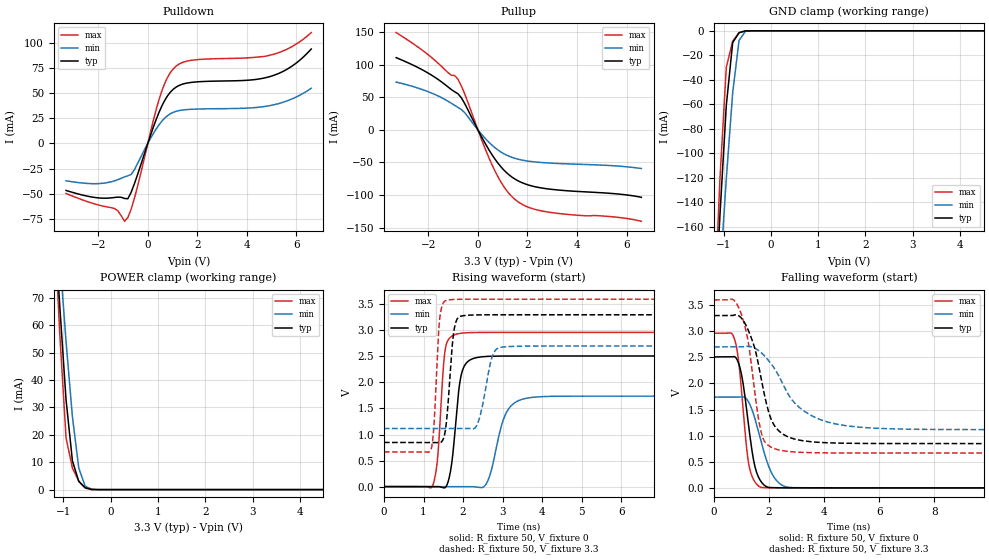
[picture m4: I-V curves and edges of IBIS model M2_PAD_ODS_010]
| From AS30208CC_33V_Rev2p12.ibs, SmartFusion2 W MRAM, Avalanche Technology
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[Model] M2_PAD_ODS_010
Model_type I/O
Enable   Active-High
Vinl  =  0.8
Vinh  =  2.2
Vmeas =  1.65
Cref  =  30e-12
| Capacitance  typ   min   max
C_comp   1.518749e-12   1.424706e-12   1.652746e-12
| Variables   typ   min   max
[GND Clamp Reference]   0   0   0
[POWER Clamp Reference]   3.3   2.7   3.6
[Pulldown Reference]   0   0   0
[Pullup Reference]   3.3   2.7   3.6
[Temperature Range]   25   125   -40
[Voltage Range]   3.3   2.7   3.6
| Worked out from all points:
|   slope of the pulldown table from 0 to 0.495 V, typ, clamps not added: 14.9 ohm
|   slope of the pullup table from 0 to 0.495 V, typ, clamps not added: 14.7 ohm
|   GND clamp passes 1 mA (typ) near -0.62 V on its own axis
|   POWER clamp passes 1 mA (typ) near -0.56 V on its own axis
|   falling waveform, R_fixture 50, V_fixture 0: 20-80 % time 394ps typ, 590ps min, 315ps max; typ from 2.51 V to 0 V
|   falling waveform, R_fixture 50, V_fixture 3.3: 20-80 % time 660ps typ, 1.32ns min, 479ps max; typ from 3.3 V to 0.848 V
|   rising waveform, R_fixture 50, V_fixture 0: 20-80 % time 197ps typ, 348ps min, 149ps max; typ from 0 V to 2.51 V
|   rising waveform, R_fixture 50, V_fixture 3.3: 20-80 % time 147ps typ, 240ps min, 115ps max; typ from 0.848 V to 3.3 V
[GND Clamp]
| Voltage   I(typ)   I(min)   I(max)
-3.3V     -1.961A    -1.697A    -2.357A
-1.21V    -250.7mA   -283.7mA   -242.5mA
-1.076V   -150.6mA   -200.1mA   -120.7mA
-941.4mV  -60.83mA   -120.8mA   -29.76mA
-806.9mV  -9.649mA   -50.71mA   -8.442mA
-672.4mV  -1.587mA   -7.866mA   -1.46mA
-537.9mV  -71.93uA   -504.3uA   -18.83uA
-403.4mV  -595.6nA   -18.58uA   -37.45nA
6.6V      0A         0A         0A
[POWER Clamp]
| Voltage   I(typ)   I(min)   I(max)
-3.3V     772.3mA    673.3mA    930.5mA
-1.21V    105.9mA    117.6mA    104.6mA
-1.076V   67.34mA    85.06mA    57.16mA
-941.4mV  32.71mA    53.93mA    18.82mA
-806.9mV  10.48mA    26.53mA    7.848mA
-672.4mV  2.975mA    7.856mA    3.108mA
-537.9mV  710.9uA    1.248mA    573.1uA
-403.4mV  60.69uA    160.8uA    9.187uA
-269mV    142.4nA    6.118uA    23.26nA
6.6V      0A         0A         0A
[Pulldown]
| Voltage   I(typ)   I(min)   I(max)
-3.3V     -46.77mA   -37.16mA   -49.83mA
-1.345V   -53.76mA   -37.21mA   -64.77mA
-941.4mV  -54.71mA   -33.33mA   -77.43mA
-806.9mV  -55.02mA   -32.17mA   -73.73mA
-537.9mV  -39.9mA    -25.92mA   -54.28mA
455.2mV   31.02mA    18.55mA    43.7mA
682.8mV   42.73mA    25.18mA    59.65mA
1.024V    53.77mA    30.89mA    74.07mA
1.821V    60.81mA    33.99mA    82.81mA
4.914V    66.31mA    37.51mA    87.55mA
5.783V    76.16mA    43.8mA     95.68mA
6.6V      93.82mA    54.81mA    110.2mA
[Pullup]
| Voltage   I(typ)   I(min)   I(max)
-3.3V     110.8mA    73.4mA     149.4mA
-1.883V   84.27mA    56.72mA    111.4mA
-806.9mV  55.48mA    34.56mA    77.7mA
-537.9mV  40.72mA    26.67mA    55.72mA
227.6mV   -16.26mA   -10.22mA   -22.67mA
682.8mV   -44.48mA   -27.12mA   -62.65mA
1.138V    -65.01mA   -38.35mA   -91.97mA
1.593V    -77.56mA   -44.65mA   -109.6mA
2.162V    -85.85mA   -48.54mA   -120.3mA
2.845V    -90.61mA   -50.73mA   -126.1mA
5.534V    -97.91mA   -55.15mA   -133.7mA
6.6V      -103.4mA   -59.29mA   -140.2mA
[Ramp]
dV/dt_r   1.50494/0.197293n  1.04234/0.347547n  1.77705/0.14905n
dV/dt_f   1.47118/0.66022n  0.951015/1.316n  1.76015/0.479444n
R_load = 50
[Falling Waveform]
R_fixture = 50
V_fixture = 0
V_fixture_min = 0
V_fixture_max = 0
| Time   V(typ)   V(min)   V(max)
0s        2.508V     1.737V     2.962V
759.6ps   2.508V     1.738V     2.821V
890.4ps   2.387V     1.738V     2.436V
999.8ps   2.164V     1.741V     1.857V
1.254ns   1.197V     1.646V     471.7mV
1.462ns   460.6mV    1.364V     132.2mV
1.72ns    111.8mV    859.7mV    7.736mV
2.149ns   3.807mV    230.1mV    1.501mV
2.718ns   1.059mV    9.353mV    845.9uV
21.88ns   537.2nV    325.5nV    -804nV
[Falling Waveform]
R_fixture = 50
V_fixture = 3.3
V_fixture_min = 2.7
V_fixture_max = 3.6
| Time   V(typ)   V(min)   V(max)
0s        3.3V       2.7V       3.6V
659.1ps   3.3V       2.7V       3.614V
907.4ps   3.292V     2.701V     3.438V
1.244ns   3.017V     2.711V     2.79V
1.71ns    2.099V     2.591V     1.067V
2ns       1.425V     2.426V     802.7mV
2.308ns   1.117V     2.186V     732.6mV
3.226ns   902.4mV    1.487V     679.2mV
4.9ns     853.7mV    1.183V     667.3mV
21.88ns   848mV      1.115V     666.4mV
[Rising Waveform]
R_fixture = 50
V_fixture = 0
V_fixture_min = 0
V_fixture_max = 0
| Time   V(typ)   V(min)   V(max)
0s        5.777nV    44.9nV     -42.68nV
1.217ns   886.5uV    -289.8uV   -4.263mV
1.357ns   1.052mV    -323.2uV   556.4mV
1.551ns   -16.19mV   -369.6uV   2.647V
1.711ns   437.6mV    -407.7uV   2.887V
1.916ns   1.993V     -456.6uV   2.942V
2.553ns   2.498V     17.69mV    2.961V
3.099ns   2.508V     1.428V     2.962V
3.73ns    2.508V     1.712V     2.962V
21.88ns   2.508V     1.737V     2.962V
[Rising Waveform]
R_fixture = 50
V_fixture = 3.3
V_fixture_min = 2.7
V_fixture_max = 3.6
| Time   V(typ)   V(min)   V(max)
0s        848mV      1.115V     666.4mV
1.189ns   847.3mV    1.116V     714.5mV
1.41ns    844.8mV    1.116V     3.235V
1.604ns   1.442V     1.116V     3.581V
1.773ns   3.011V     1.116V     3.594V
2.021ns   3.283V     1.116V     3.599V
2.351ns   3.297V     1.183V     3.599V
2.742ns   3.299V     2.508V     3.599V
3.026ns   3.299V     2.682V     3.599V
21.88ns   3.3V       2.7V       3.6V
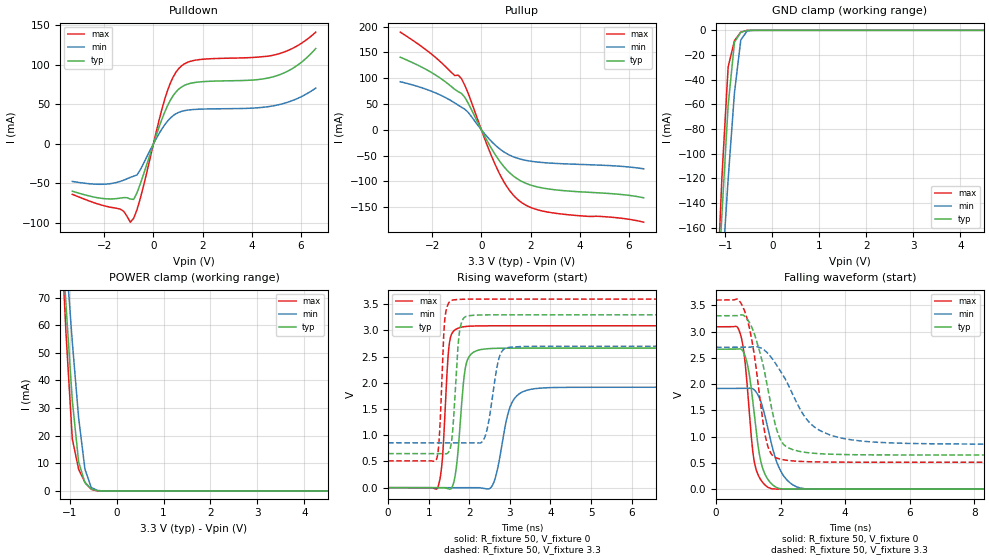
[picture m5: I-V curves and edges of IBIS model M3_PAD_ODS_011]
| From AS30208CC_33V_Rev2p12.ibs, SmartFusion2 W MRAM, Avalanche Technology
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[Model] M3_PAD_ODS_011
Model_type I/O
Enable   Active-High
Vinl  =  0.8
Vinh  =  2.2
Vmeas =  1.65
Cref  =  30e-12
| Capacitance  typ   min   max
C_comp   1.518749e-12   1.424706e-12   1.652746e-12
| Variables   typ   min   max
[GND Clamp Reference]   0   0   0
[POWER Clamp Reference]   3.3   2.7   3.6
[Pulldown Reference]   0   0   0
[Pullup Reference]   3.3   2.7   3.6
[Temperature Range]   25   125   -40
[Voltage Range]   3.3   2.7   3.6
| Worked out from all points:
|   slope of the pulldown table from 0 to 0.495 V, typ, clamps not added: 11.6 ohm
|   slope of the pullup table from 0 to 0.495 V, typ, clamps not added: 11.6 ohm
|   GND clamp passes 1 mA (typ) near -0.62 V on its own axis
|   POWER clamp passes 1 mA (typ) near -0.56 V on its own axis
|   falling waveform, R_fixture 50, V_fixture 0: 20-80 % time 343ps typ, 517ps min, 271ps max; typ from 2.66 V to 0 V
|   falling waveform, R_fixture 50, V_fixture 3.3: 20-80 % time 577ps typ, 1.06ns min, 432ps max; typ from 3.3 V to 0.65 V
|   rising waveform, R_fixture 50, V_fixture 0: 20-80 % time 171ps typ, 299ps min, 130ps max; typ from 0 V to 2.66 V
|   rising waveform, R_fixture 50, V_fixture 3.3: 20-80 % time 129ps typ, 221ps min, 101ps max; typ from 0.65 V to 3.3 V
[GND Clamp]
| Voltage   I(typ)   I(min)   I(max)
-3.3V     -1.961A    -1.697A    -2.357A
-1.21V    -250.7mA   -283.7mA   -242.5mA
-1.076V   -150.6mA   -200.1mA   -120.7mA
-941.4mV  -60.83mA   -120.8mA   -29.76mA
-806.9mV  -9.649mA   -50.71mA   -8.442mA
-672.4mV  -1.587mA   -7.866mA   -1.46mA
-537.9mV  -71.93uA   -504.3uA   -18.83uA
-403.4mV  -595.6nA   -18.58uA   -37.45nA
6.6V      0A         0A         0A
[POWER Clamp]
| Voltage   I(typ)   I(min)   I(max)
-3.3V     772.3mA    673.3mA    930.5mA
-1.21V    105.9mA    117.6mA    104.6mA
-1.076V   67.34mA    85.06mA    57.16mA
-941.4mV  32.71mA    53.93mA    18.82mA
-806.9mV  10.48mA    26.53mA    7.848mA
-672.4mV  2.975mA    7.856mA    3.108mA
-537.9mV  710.9uA    1.248mA    573.1uA
-403.4mV  60.69uA    160.8uA    9.187uA
-269mV    142.4nA    6.118uA    23.26nA
6.6V      0A         0A         0A
[Pulldown]
| Voltage   I(typ)   I(min)   I(max)
-3.3V     -60.24mA   -47.82mA   -64.23mA
-1.345V   -68.96mA   -47.76mA   -83.06mA
-941.4mV  -70.11mA   -42.69mA   -99.52mA
-806.9mV  -70.67mA   -41.24mA   -94.66mA
-537.9mV  -51.24mA   -33.31mA   -69.64mA
455.2mV   39.84mA    23.83mA    56.08mA
682.8mV   54.89mA    32.35mA    76.58mA
1.024V    69.09mA    39.7mA     95.16mA
1.821V    78.16mA    43.68mA    106.4mA
4.914V    85.23mA    48.22mA    112.5mA
5.783V    97.9mA     56.32mA    122.9mA
6.6V      120.6mA    70.51mA    141.5mA
[Pullup]
| Voltage   I(typ)   I(min)   I(max)
-3.3V     140.6mA    93.2mA     189.3mA
-1.883V   106.7mA    71.93mA    140.9mA
-1.076V   78.15mA    51.9mA     105.1mA
-941.4mV  73.93mA    47.76mA    105.9mA
-806.9mV  70.38mA    43.76mA    98.84mA
-537.9mV  51.76mA    33.91mA    70.85mA
227.6mV   -20.67mA   -12.99mA   -28.83mA
682.8mV   -56.54mA   -34.48mA   -79.66mA
1.138V    -82.63mA   -48.76mA   -116.9mA
1.593V    -98.59mA   -56.76mA   -139.3mA
2.731V    -114.5mA   -64.15mA   -159.5mA
6.6V      -131.6mA   -75.43mA   -178.8mA
[Ramp]
dV/dt_r   1.59832/0.171426n  1.14988/0.298556n  1.85402/0.129888n
dV/dt_f   1.58991/0.57709n  1.10595/1.05796n  1.85298/0.431635n
R_load = 50
[Falling Waveform]
R_fixture = 50
V_fixture = 0
V_fixture_min = 0
V_fixture_max = 0
| Time   V(typ)   V(min)   V(max)
0s        2.664V     1.916V     3.09V
739.8ps   2.671V     1.917V     2.983V
866.3ps   2.589V     1.917V     2.599V
968.5ps   2.389V     1.918V     1.967V
1.189ns   1.411V     1.889V     516.5mV
1.4ns     500.3mV    1.647V     166.1mV
1.721ns   102.4mV    861.2mV    8.015mV
2.125ns   3.601mV    228.9mV    1.346mV
2.749ns   988.9uV    8.253mV    703.6uV
21.88ns   652.4nV    538.1nV    -524.3nV
[Falling Waveform]
R_fixture = 50
V_fixture = 3.3
V_fixture_min = 2.7
V_fixture_max = 3.6
| Time   V(typ)   V(min)   V(max)
0s        3.3V       2.7V       3.6V
663ps     3.301V     2.701V     3.616V
867.2ps   3.302V     2.701V     3.421V
1.163ns   3.001V     2.713V     2.652V
1.556ns   2.074V     2.615V     933.4mV
1.834ns   1.239V     2.403V     603.8mV
2.018ns   922mV      2.229V     568mV
2.965ns   686.7mV    1.227V     520.5mV
4.374ns   655.1mV    924.2mV    512.6mV
21.88ns   650.1mV    856.7mV    511.7mV
[Rising Waveform]
R_fixture = 50
V_fixture = 0
V_fixture_min = 0
V_fixture_max = 0
| Time   V(typ)   V(min)   V(max)
0s        4.898nV    37.59nV    -5.714nV
1.225ns   858.3uV    541.9uV    8.251mV
1.333ns   933.8uV    589.5uV    501.5mV
1.512ns   -27.46mV   669uV      2.769V
1.681ns   377.8mV    743.4uV    3.028V
1.856ns   1.998V     821.1uV    3.07V
2.551ns   2.657V     18.05mV    3.09V
3.031ns   2.663V     1.587V     3.09V
3.633ns   2.664V     1.891V     3.09V
21.88ns   2.664V     1.916V     3.09V
[Rising Waveform]
R_fixture = 50
V_fixture = 3.3
V_fixture_min = 2.7
V_fixture_max = 3.6
| Time   V(typ)   V(min)   V(max)
0s        650.1mV    856.8mV    511.7mV
1.196ns   651mV      856.4mV    548.6mV
1.398ns   647.8mV    856.3mV    3.212V
1.6ns     1.164V     856.2mV    3.582V
1.76ns    2.974V     856.2mV    3.594V
2.021ns   3.284V     856.1mV    3.599V
2.373ns   3.298V     944.5mV    3.599V
2.727ns   3.299V     2.455V     3.599V
3.008ns   3.299V     2.68V      3.599V
21.88ns   3.3V       2.7V       3.6V
